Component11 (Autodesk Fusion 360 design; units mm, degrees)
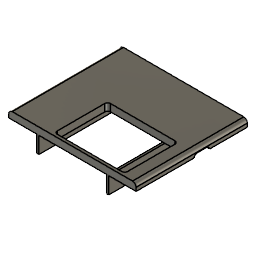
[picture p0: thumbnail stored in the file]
base_feature "Base Feature"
